VERSION 5.7 ;
  NOWIREEXTENSIONATPIN ON ;
  DIVIDERCHAR "/" ;
  BUSBITCHARS "[]" ;
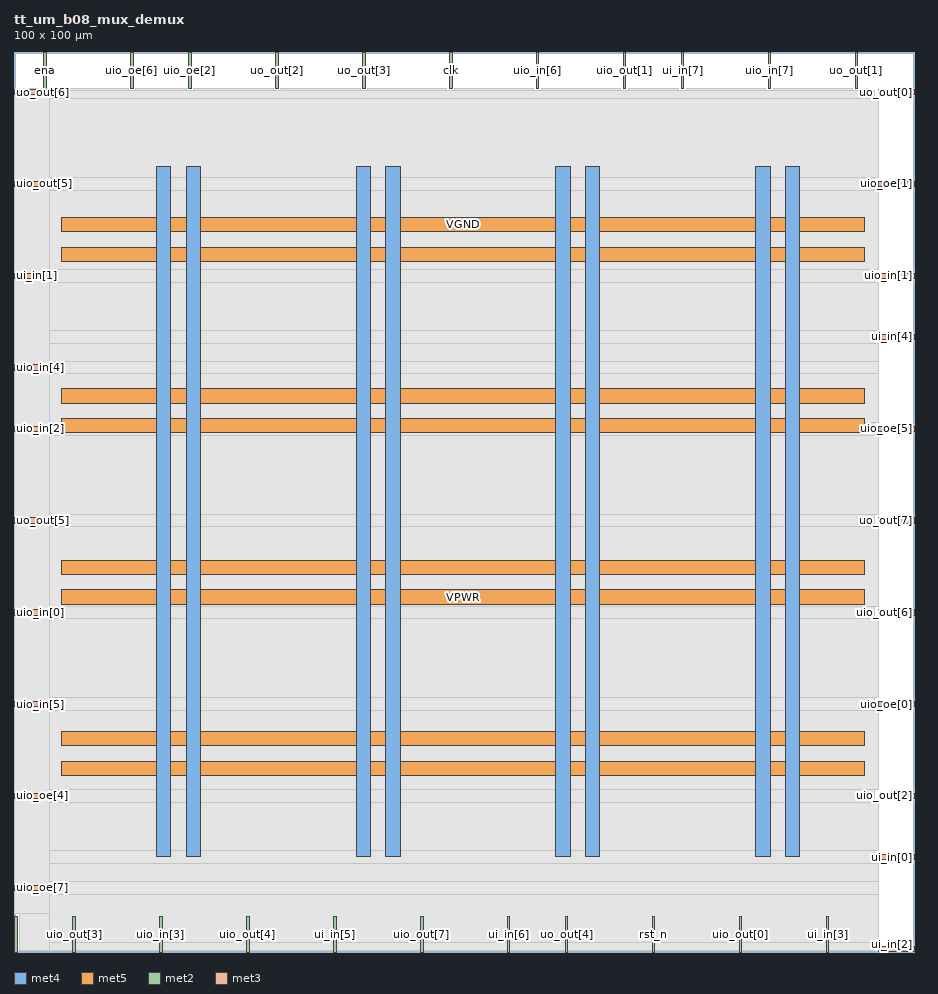
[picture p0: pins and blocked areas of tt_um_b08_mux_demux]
MACRO tt_um_b08_mux_demux
  CLASS BLOCK ;
  FOREIGN tt_um_b08_mux_demux ;
  ORIGIN 0.000 0.000 ;
  SIZE 100.000 BY 100.000 ;
  PIN VGND
    DIRECTION INOUT ;
    USE GROUND ;
    PORT
      LAYER met4 ;
        RECT 19.115 10.640 20.715 87.280 ;
    END
    PORT
      LAYER met4 ;
        RECT 41.310 10.640 42.910 87.280 ;
    END
    PORT
      LAYER met4 ;
        RECT 63.505 10.640 65.105 87.280 ;
    END
    PORT
      LAYER met4 ;
        RECT 85.700 10.640 87.300 87.280 ;
    END
    PORT
      LAYER met5 ;
        RECT 5.280 22.900 94.540 24.500 ;
    END
    PORT
      LAYER met5 ;
        RECT 5.280 41.940 94.540 43.540 ;
    END
    PORT
      LAYER met5 ;
        RECT 5.280 60.980 94.540 62.580 ;
    END
    PORT
      LAYER met5 ;
        RECT 5.280 80.020 94.540 81.620 ;
    END
  END VGND
  PIN VPWR
    DIRECTION INOUT ;
    USE POWER ;
    PORT
      LAYER met4 ;
        RECT 15.815 10.640 17.415 87.280 ;
    END
    PORT
      LAYER met4 ;
        RECT 38.010 10.640 39.610 87.280 ;
    END
    PORT
      LAYER met4 ;
        RECT 60.205 10.640 61.805 87.280 ;
    END
    PORT
      LAYER met4 ;
        RECT 82.400 10.640 84.000 87.280 ;
    END
    PORT
      LAYER met5 ;
        RECT 5.280 19.600 94.540 21.200 ;
    END
    PORT
      LAYER met5 ;
        RECT 5.280 38.640 94.540 40.240 ;
    END
    PORT
      LAYER met5 ;
        RECT 5.280 57.680 94.540 59.280 ;
    END
    PORT
      LAYER met5 ;
        RECT 5.280 76.720 94.540 78.320 ;
    END
  END VPWR
  PIN clk
    DIRECTION INPUT ;
    USE SIGNAL ;
    PORT
      LAYER met2 ;
        RECT 48.390 96.000 48.670 100.000 ;
    END
  END clk
  PIN ena
    DIRECTION INPUT ;
    USE SIGNAL ;
    PORT
      LAYER met2 ;
        RECT 3.310 96.000 3.590 100.000 ;
    END
  END ena
  PIN rst_n
    DIRECTION INPUT ;
    USE SIGNAL ;
    PORT
      LAYER met2 ;
        RECT 70.930 0.000 71.210 4.000 ;
    END
  END rst_n
  PIN ui_in[0]
    DIRECTION INPUT ;
    USE SIGNAL ;
    ANTENNAGATEAREA 0.196500 ;
    PORT
      LAYER met3 ;
        RECT 96.000 10.240 100.000 10.840 ;
    END
  END ui_in[0]
  PIN ui_in[1]
    DIRECTION INPUT ;
    USE SIGNAL ;
    ANTENNAGATEAREA 0.196500 ;
    PORT
      LAYER met3 ;
        RECT 0.000 74.840 4.000 75.440 ;
    END
  END ui_in[1]
  PIN ui_in[2]
    DIRECTION INPUT ;
    USE SIGNAL ;
    ANTENNAGATEAREA 0.196500 ;
    PORT
      LAYER met3 ;
        RECT 96.000 0.040 100.000 0.640 ;
    END
  END ui_in[2]
  PIN ui_in[3]
    DIRECTION INPUT ;
    USE SIGNAL ;
    ANTENNAGATEAREA 0.196500 ;
    PORT
      LAYER met2 ;
        RECT 90.250 0.000 90.530 4.000 ;
    END
  END ui_in[3]
  PIN ui_in[4]
    DIRECTION INPUT ;
    USE SIGNAL ;
    ANTENNAGATEAREA 0.196500 ;
    PORT
      LAYER met3 ;
        RECT 96.000 68.040 100.000 68.640 ;
    END
  END ui_in[4]
  PIN ui_in[5]
    DIRECTION INPUT ;
    USE SIGNAL ;
    ANTENNAGATEAREA 0.196500 ;
    PORT
      LAYER met2 ;
        RECT 35.510 0.000 35.790 4.000 ;
    END
  END ui_in[5]
  PIN ui_in[6]
    DIRECTION INPUT ;
    USE SIGNAL ;
    ANTENNAGATEAREA 0.196500 ;
    PORT
      LAYER met2 ;
        RECT 54.830 0.000 55.110 4.000 ;
    END
  END ui_in[6]
  PIN ui_in[7]
    DIRECTION INPUT ;
    USE SIGNAL ;
    ANTENNAGATEAREA 0.196500 ;
    PORT
      LAYER met2 ;
        RECT 74.150 96.000 74.430 100.000 ;
    END
  END ui_in[7]
  PIN uio_in[0]
    DIRECTION INPUT ;
    USE SIGNAL ;
    ANTENNAGATEAREA 0.196500 ;
    PORT
      LAYER met3 ;
        RECT 0.000 37.440 4.000 38.040 ;
    END
  END uio_in[0]
  PIN uio_in[1]
    DIRECTION INPUT ;
    USE SIGNAL ;
    ANTENNAGATEAREA 0.159000 ;
    PORT
      LAYER met3 ;
        RECT 96.000 74.840 100.000 75.440 ;
    END
  END uio_in[1]
  PIN uio_in[2]
    DIRECTION INPUT ;
    USE SIGNAL ;
    ANTENNAGATEAREA 0.213000 ;
    PORT
      LAYER met3 ;
        RECT 0.000 57.840 4.000 58.440 ;
    END
  END uio_in[2]
  PIN uio_in[3]
    DIRECTION INPUT ;
    USE SIGNAL ;
    ANTENNAGATEAREA 0.159000 ;
    PORT
      LAYER met2 ;
        RECT 16.190 0.000 16.470 4.000 ;
    END
  END uio_in[3]
  PIN uio_in[4]
    DIRECTION INPUT ;
    USE SIGNAL ;
    PORT
      LAYER met3 ;
        RECT 0.000 64.640 4.000 65.240 ;
    END
  END uio_in[4]
  PIN uio_in[5]
    DIRECTION INPUT ;
    USE SIGNAL ;
    PORT
      LAYER met3 ;
        RECT 0.000 27.240 4.000 27.840 ;
    END
  END uio_in[5]
  PIN uio_in[6]
    DIRECTION INPUT ;
    USE SIGNAL ;
    PORT
      LAYER met2 ;
        RECT 58.050 96.000 58.330 100.000 ;
    END
  END uio_in[6]
  PIN uio_in[7]
    DIRECTION INPUT ;
    USE SIGNAL ;
    PORT
      LAYER met2 ;
        RECT 83.810 96.000 84.090 100.000 ;
    END
  END uio_in[7]
  PIN uio_oe[0]
    DIRECTION OUTPUT TRISTATE ;
    USE SIGNAL ;
    PORT
      LAYER met3 ;
        RECT 96.000 27.240 100.000 27.840 ;
    END
  END uio_oe[0]
  PIN uio_oe[1]
    DIRECTION OUTPUT TRISTATE ;
    USE SIGNAL ;
    PORT
      LAYER met3 ;
        RECT 96.000 85.040 100.000 85.640 ;
    END
  END uio_oe[1]
  PIN uio_oe[2]
    DIRECTION OUTPUT TRISTATE ;
    USE SIGNAL ;
    PORT
      LAYER met2 ;
        RECT 19.410 96.000 19.690 100.000 ;
    END
  END uio_oe[2]
  PIN uio_oe[3]
    DIRECTION OUTPUT TRISTATE ;
    USE SIGNAL ;
    PORT
      LAYER met2 ;
        RECT 0.090 0.000 0.370 4.000 ;
    END
  END uio_oe[3]
  PIN uio_oe[4]
    DIRECTION OUTPUT TRISTATE ;
    USE SIGNAL ;
    PORT
      LAYER met3 ;
        RECT 0.000 17.040 4.000 17.640 ;
    END
  END uio_oe[4]
  PIN uio_oe[5]
    DIRECTION OUTPUT TRISTATE ;
    USE SIGNAL ;
    PORT
      LAYER met3 ;
        RECT 96.000 57.840 100.000 58.440 ;
    END
  END uio_oe[5]
  PIN uio_oe[6]
    DIRECTION OUTPUT TRISTATE ;
    USE SIGNAL ;
    PORT
      LAYER met2 ;
        RECT 12.970 96.000 13.250 100.000 ;
    END
  END uio_oe[6]
  PIN uio_oe[7]
    DIRECTION OUTPUT TRISTATE ;
    USE SIGNAL ;
    PORT
      LAYER met3 ;
        RECT 0.000 6.840 4.000 7.440 ;
    END
  END uio_oe[7]
  PIN uio_out[0]
    DIRECTION OUTPUT TRISTATE ;
    USE SIGNAL ;
    PORT
      LAYER met2 ;
        RECT 80.590 0.000 80.870 4.000 ;
    END
  END uio_out[0]
  PIN uio_out[1]
    DIRECTION OUTPUT TRISTATE ;
    USE SIGNAL ;
    PORT
      LAYER met2 ;
        RECT 67.710 96.000 67.990 100.000 ;
    END
  END uio_out[1]
  PIN uio_out[2]
    DIRECTION OUTPUT TRISTATE ;
    USE SIGNAL ;
    PORT
      LAYER met3 ;
        RECT 96.000 17.040 100.000 17.640 ;
    END
  END uio_out[2]
  PIN uio_out[3]
    DIRECTION OUTPUT TRISTATE ;
    USE SIGNAL ;
    PORT
      LAYER met2 ;
        RECT 6.530 0.000 6.810 4.000 ;
    END
  END uio_out[3]
  PIN uio_out[4]
    DIRECTION OUTPUT TRISTATE ;
    USE SIGNAL ;
    PORT
      LAYER met2 ;
        RECT 25.850 0.000 26.130 4.000 ;
    END
  END uio_out[4]
  PIN uio_out[5]
    DIRECTION OUTPUT TRISTATE ;
    USE SIGNAL ;
    PORT
      LAYER met3 ;
        RECT 0.000 85.040 4.000 85.640 ;
    END
  END uio_out[5]
  PIN uio_out[6]
    DIRECTION OUTPUT TRISTATE ;
    USE SIGNAL ;
    PORT
      LAYER met3 ;
        RECT 96.000 37.440 100.000 38.040 ;
    END
  END uio_out[6]
  PIN uio_out[7]
    DIRECTION OUTPUT TRISTATE ;
    USE SIGNAL ;
    PORT
      LAYER met2 ;
        RECT 45.170 0.000 45.450 4.000 ;
    END
  END uio_out[7]
  PIN uo_out[0]
    DIRECTION OUTPUT TRISTATE ;
    USE SIGNAL ;
    ANTENNADIFFAREA 0.795200 ;
    PORT
      LAYER met3 ;
        RECT 96.000 95.240 100.000 95.840 ;
    END
  END uo_out[0]
  PIN uo_out[1]
    DIRECTION OUTPUT TRISTATE ;
    USE SIGNAL ;
    ANTENNADIFFAREA 0.795200 ;
    PORT
      LAYER met2 ;
        RECT 93.470 96.000 93.750 100.000 ;
    END
  END uo_out[1]
  PIN uo_out[2]
    DIRECTION OUTPUT TRISTATE ;
    USE SIGNAL ;
    ANTENNADIFFAREA 0.795200 ;
    PORT
      LAYER met2 ;
        RECT 29.070 96.000 29.350 100.000 ;
    END
  END uo_out[2]
  PIN uo_out[3]
    DIRECTION OUTPUT TRISTATE ;
    USE SIGNAL ;
    ANTENNADIFFAREA 0.795200 ;
    PORT
      LAYER met2 ;
        RECT 38.730 96.000 39.010 100.000 ;
    END
  END uo_out[3]
  PIN uo_out[4]
    DIRECTION OUTPUT TRISTATE ;
    USE SIGNAL ;
    ANTENNADIFFAREA 0.795200 ;
    PORT
      LAYER met2 ;
        RECT 61.270 0.000 61.550 4.000 ;
    END
  END uo_out[4]
  PIN uo_out[5]
    DIRECTION OUTPUT TRISTATE ;
    USE SIGNAL ;
    ANTENNADIFFAREA 0.795200 ;
    PORT
      LAYER met3 ;
        RECT 0.000 47.640 4.000 48.240 ;
    END
  END uo_out[5]
  PIN uo_out[6]
    DIRECTION OUTPUT TRISTATE ;
    USE SIGNAL ;
    ANTENNADIFFAREA 0.795200 ;
    PORT
      LAYER met3 ;
        RECT 0.000 95.240 4.000 95.840 ;
    END
  END uo_out[6]
  PIN uo_out[7]
    DIRECTION OUTPUT TRISTATE ;
    USE SIGNAL ;
    ANTENNADIFFAREA 0.795200 ;
    PORT
      LAYER met3 ;
        RECT 96.000 47.640 100.000 48.240 ;
    END
  END uo_out[7]
  OBS
      LAYER li1 ;
        RECT 5.520 10.795 94.300 87.125 ;
      LAYER met1 ;
        RECT 0.070 10.640 95.150 87.280 ;
      LAYER met2 ;
        RECT 0.100 95.720 3.030 96.000 ;
        RECT 3.870 95.720 12.690 96.000 ;
        RECT 13.530 95.720 19.130 96.000 ;
        RECT 19.970 95.720 28.790 96.000 ;
        RECT 29.630 95.720 38.450 96.000 ;
        RECT 39.290 95.720 48.110 96.000 ;
        RECT 48.950 95.720 57.770 96.000 ;
        RECT 58.610 95.720 67.430 96.000 ;
        RECT 68.270 95.720 73.870 96.000 ;
        RECT 74.710 95.720 83.530 96.000 ;
        RECT 84.370 95.720 93.190 96.000 ;
        RECT 94.030 95.720 95.130 96.000 ;
        RECT 0.100 4.280 95.130 95.720 ;
        RECT 0.650 0.155 6.250 4.280 ;
        RECT 7.090 0.155 15.910 4.280 ;
        RECT 16.750 0.155 25.570 4.280 ;
        RECT 26.410 0.155 35.230 4.280 ;
        RECT 36.070 0.155 44.890 4.280 ;
        RECT 45.730 0.155 54.550 4.280 ;
        RECT 55.390 0.155 60.990 4.280 ;
        RECT 61.830 0.155 70.650 4.280 ;
        RECT 71.490 0.155 80.310 4.280 ;
        RECT 81.150 0.155 89.970 4.280 ;
        RECT 90.810 0.155 95.130 4.280 ;
      LAYER met3 ;
        RECT 4.400 94.840 95.600 95.705 ;
        RECT 3.990 86.040 96.000 94.840 ;
        RECT 4.400 84.640 95.600 86.040 ;
        RECT 3.990 75.840 96.000 84.640 ;
        RECT 4.400 74.440 95.600 75.840 ;
        RECT 3.990 69.040 96.000 74.440 ;
        RECT 3.990 67.640 95.600 69.040 ;
        RECT 3.990 65.640 96.000 67.640 ;
        RECT 4.400 64.240 96.000 65.640 ;
        RECT 3.990 58.840 96.000 64.240 ;
        RECT 4.400 57.440 95.600 58.840 ;
        RECT 3.990 48.640 96.000 57.440 ;
        RECT 4.400 47.240 95.600 48.640 ;
        RECT 3.990 38.440 96.000 47.240 ;
        RECT 4.400 37.040 95.600 38.440 ;
        RECT 3.990 28.240 96.000 37.040 ;
        RECT 4.400 26.840 95.600 28.240 ;
        RECT 3.990 18.040 96.000 26.840 ;
        RECT 4.400 16.640 95.600 18.040 ;
        RECT 3.990 11.240 96.000 16.640 ;
        RECT 3.990 9.840 95.600 11.240 ;
        RECT 3.990 7.840 96.000 9.840 ;
        RECT 4.400 6.440 96.000 7.840 ;
        RECT 3.990 1.040 96.000 6.440 ;
        RECT 3.990 0.175 95.600 1.040 ;
  END
END tt_um_b08_mux_demux
END LIBRARY

